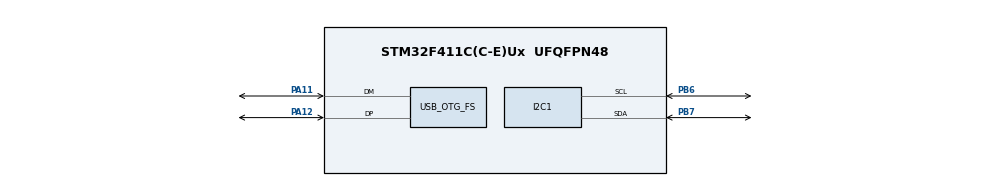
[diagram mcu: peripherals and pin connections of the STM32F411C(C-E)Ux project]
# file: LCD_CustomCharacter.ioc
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Mcu.Family=STM32F4
Mcu.Name=STM32F411C(C-E)Ux
Mcu.Package=UFQFPN48
NVIC.OTG_FS_IRQn=true\:0\:0\:false\:false\:true\:false\:true\:true
NVIC.PriorityGroup=NVIC_PRIORITYGROUP_4
PA11.Mode=Device_Only
PA11.Signal=USB_OTG_FS_DM
PA12.Mode=Device_Only
PA12.Signal=USB_OTG_FS_DP
PA13.Mode=Serial_Wire
PA13.Signal=SYS_JTMS-SWDIO
PA14.Mode=Serial_Wire
PA14.Signal=SYS_JTCK-SWCLK
PB6.Mode=I2C
PB6.Signal=I2C1_SCL
PB7.Mode=I2C
PB7.Signal=I2C1_SDA
PH0\ -\ OSC_IN.Mode=HSE-External-Oscillator
PH0\ -\ OSC_IN.Signal=RCC_OSC_IN
PH1\ -\ OSC_OUT.Mode=HSE-External-Oscillator
PH1\ -\ OSC_OUT.Signal=RCC_OSC_OUT
ProjectManager.HeapSize=0x200
ProjectManager.StackSize=0x400
ProjectManager.TargetToolchain=STM32CubeIDE
RCC.48MHZClocksFreq_Value=48000000
RCC.AHBFreq_Value=25000000
RCC.APB1CLKDivider=RCC_HCLK_DIV2
RCC.APB1Freq_Value=12500000
RCC.APB1TimFreq_Value=25000000
RCC.APB2Freq_Value=25000000
RCC.APB2TimFreq_Value=25000000
RCC.CortexFreq_Value=25000000
RCC.HCLKFreq_Value=25000000
RCC.HSE_VALUE=25000000
RCC.HSI_VALUE=16000000
RCC.LSE_VALUE=32768
RCC.PLLM=15
RCC.PLLN=144
RCC.PLLQ=5
RCC.SYSCLKFreq_VALUE=25000000
RCC.SYSCLKSource=RCC_SYSCLKSOURCE_HSE
RCC.VCOOutputFreq_Value=240000000
USB_DEVICE.CLASS_NAME_FS=CDC
USB_DEVICE.VirtualMode=Cdc
USB_DEVICE.VirtualModeFS=Cdc_FS
USB_OTG_FS.VirtualMode=Device_Only
VP_USB_DEVICE_VS_USB_DEVICE_CDC_FS.Mode=CDC_FS
board=custom

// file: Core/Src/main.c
/* USER CODE BEGIN Header */
/**
 ******************************************************************************
 * @file           : main.c
 * @brief          : Main program body
 ******************************************************************************
 * @attention
 *
 * Copyright (c) 2024 STMicroelectronics.
 * All rights reserved.
 *
 * This software is licensed under terms that can be found in the LICENSE file
 * in the root directory of this software component.
 * If no LICENSE file comes with this software, it is provided AS-IS.
 *
 ******************************************************************************
 */
/* USER CODE END Header */
#include "main.h"
#include "usb_device.h"

/* USER CODE BEGIN Includes */
#include "count2volt.h"
/* USER CODE END Includes */

/* USER CODE BEGIN PD */
#define END_I2C 0x27
#define Linha_1 (0x80 | 0x00)
#define Linha_2 (0x80 | 0x40)
#define Linha_3 (0x80 | 0x14)
#define Linha_4 (0x80 | 0x54)
#define ADCRES 12
/* USER CODE END PD */

I2C_HandleTypeDef hi2c1;

void SystemClock_Config(void);
static void MX_GPIO_Init(void);
static void MX_I2C1_Init(void);
/* USER CODE BEGIN PFP */
void create_custom_char (uint8_t loc, char *data);
void display_custom_char (uint8_t loc);
/* USER CODE END PFP */

int main(void) {

	/* MCU Configuration--------------------------------------------------------*/

	/* Reset of all peripherals, Initializes the Flash interface and the Systick. */
	HAL_Init();

	/* Configure the system clock */
	SystemClock_Config();

	/* Initialize all configured peripherals */
	MX_GPIO_Init();
	MX_I2C1_Init();
	MX_USB_DEVICE_Init();
	lcd_init();
	/* USER CODE BEGIN 2 */

	lcd_clear();

/*

	char cc1[] = { 0x00, 0x00, 0x0A, 0x00, 0x11, 0x0E, 0x00, 0x00 };  // smiley
	char cc2[] = { 0x0E, 0x0E, 0x04, 0x0E, 0x15, 0x04, 0x0A, 0x0A };  // Robo
	char cc3[] = { 0x08, 0x0C, 0x0E, 0x0F, 0x0E, 0x0C, 0x08, 0x00 };  // arrow
	char cc4[] = { 0x00, 0x04, 0x0E, 0x0E, 0x0E, 0x1F, 0x04, 0x00 };  // bell
	char cc5[] = { 0x00, 0x00, 0x0A, 0x15, 0x11, 0x0E, 0x04, 0x00 };  // Heart
	char cc6[] = { 0x00, 0x0E, 0x11, 0x11, 0x11, 0x0A, 0x1B, 0x00 };  // omega
	char cc7[] = { 0x0E, 0x10, 0x17, 0x12, 0x12, 0x12, 0x10, 0x0E };  // CT
	char cc8[] = { 0x04, 0x04, 0x1F, 0x04, 0x04, 0x00, 0x1F, 0x00 };  // +-

*/

	const char glyphs[][8] = { // Each is an eighth of the number digit                        // Custom character definitions
	      { 0x1F, 0x1F, 0x1F, 0x00, 0x00, 0x00, 0x00, 0x00 }, // char 1
	      { 0x18, 0x1C, 0x1E, 0x1F, 0x1F, 0x1F, 0x1F, 0x1F }, // char 2
	      { 0x1F, 0x1F, 0x1F, 0x1F, 0x1F, 0x0F, 0x07, 0x03 }, // char 3
	      { 0x00, 0x00, 0x00, 0x00, 0x00, 0x1F, 0x1F, 0x1F }, // char 4
	      { 0x1F, 0x1F, 0x1F, 0x1F, 0x1F, 0x1E, 0x1C, 0x18 }, // char 5
	      { 0x1F, 0x1F, 0x1F, 0x00, 0x00, 0x00, 0x1F, 0x1F }, // char 6
	      { 0x1F, 0x00, 0x00, 0x00, 0x00, 0x1F, 0x1F, 0x1F }, // char 7
	      { 0x03, 0x07, 0x0F, 0x1F, 0x1F, 0x1F, 0x1F, 0x1F }  // char 8
	};

	create_custom_char(0, glyphs[0]);
	create_custom_char(1, glyphs[1]);
	create_custom_char(2, glyphs[2]);
	create_custom_char(3, glyphs[3]);
	create_custom_char(4, glyphs[4]);
	create_custom_char(5, glyphs[5]);
	create_custom_char(6, glyphs[6]);
	create_custom_char(7, glyphs[7]);

/*

	lcd_put_cur(0, 0);
	lcd_send_string("Custom characters");
	HAL_Delay(200);
	lcd_put_cur(1, 1);

*/
	lcd_put_cur(0, 0);
	display_custom_char(7);
	lcd_put_cur(0,1);
	display_custom_char(0);
	lcd_put_cur(0, 2);
	display_custom_char(1);
	lcd_put_cur(1,0);
	display_custom_char(2);
	lcd_put_cur(1, 1);
	display_custom_char(3);
	lcd_put_cur(1, 2);
	display_custom_char(4);

/*	for (int i = 0; i < 8; i++) {
		display_custom_char(i);
		HAL_Delay(300);
	}*/

	//HAL_Delay(1000);
	//lcd_clear();
	//HAL_Delay(1000);

/*

	// store the chars into the CGRAM
	lcd_send_cmd(0x40);
	for (int i = 0; i < 8; i++)
		lcd_send_data(cc1[i]);

	lcd_send_cmd(0x40 + 8);
	for (int i = 0; i < 8; i++)
		lcd_send_data(cc2[i]);

	lcd_send_cmd(0x40 + 16);
	for (int i = 0; i < 8; i++)
		lcd_send_data(cc3[i]);

	lcd_send_cmd(0x40 + 24);
	for (int i = 0; i < 8; i++)
		lcd_send_data(cc4[i]);

	lcd_send_cmd(0x40 + 32);
	for (int i = 0; i < 8; i++)
		lcd_send_data(cc5[i]);

	lcd_send_cmd(0x40 + 40);
	for (int i = 0; i < 8; i++)
		lcd_send_data(cc6[i]);

	lcd_send_cmd(0x40 + 48);
	for (int i = 0; i < 8; i++)
		lcd_send_data(cc7[i]);

	lcd_send_cmd(0x40 + 56);
	for (int i = 0; i < 8; i++)
		lcd_send_data(cc8[i]);

*/

/*

	lcd_clear();

	for(int i = 0; i < 20; i++) {
		lcd_put_cur(0,i);
		lcd_send_data(0xFF);
		lcd_put_cur(3,i);
		lcd_send_data(0xFF);
	}

	for(int i = 1; i < 3; i++) {
		lcd_put_cur(i,0);
		lcd_send_data(0xFF);
		lcd_put_cur(i, 19);
		lcd_send_data(0xFF);
	}

	// A tabela de caracteres da CGROM é a ASCII 32=space [33,126] numbers, letters and some especial
	// characters
	for(int row = 1; row < 3; row++) {
		for(int column = 1; column < 19; column++) {
			for(int character = 33; character <= 90; character++) {
				lcd_put_cur(row, column);
				lcd_send_data(character);
				HAL_Delay(50);
			}
			lcd_put_cur(row, column);
			lcd_send_data(32);
		}
	}

*/

	/* USER CODE END 2 */

	/* Infinite loop */
	while (1) {

	}
}

void SystemClock_Config(void) {
	RCC_OscInitTypeDef RCC_OscInitStruct = { 0 };
	RCC_ClkInitTypeDef RCC_ClkInitStruct = { 0 };

	/** Configure the main internal regulator output voltage
	 */
	__HAL_RCC_PWR_CLK_ENABLE();
	__HAL_PWR_VOLTAGESCALING_CONFIG(PWR_REGULATOR_VOLTAGE_SCALE1);

	/** Initializes the RCC Oscillators according to the specified parameters
	 * in the RCC_OscInitTypeDef structure.
	 */
	RCC_OscInitStruct.OscillatorType = RCC_OSCILLATORTYPE_HSE;
	RCC_OscInitStruct.HSEState = RCC_HSE_ON;
	RCC_OscInitStruct.PLL.PLLState = RCC_PLL_ON;
	RCC_OscInitStruct.PLL.PLLSource = RCC_PLLSOURCE_HSE;
	RCC_OscInitStruct.PLL.PLLM = 12;
	RCC_OscInitStruct.PLL.PLLN = 96;
	RCC_OscInitStruct.PLL.PLLP = RCC_PLLP_DIV2;
	RCC_OscInitStruct.PLL.PLLQ = 4;
	if (HAL_RCC_OscConfig(&RCC_OscInitStruct) != HAL_OK) {
		Error_Handler();
	}

	/** Initializes the CPU, AHB and APB buses clocks
	 */
	RCC_ClkInitStruct.ClockType = RCC_CLOCKTYPE_HCLK | RCC_CLOCKTYPE_SYSCLK
			| RCC_CLOCKTYPE_PCLK1 | RCC_CLOCKTYPE_PCLK2;
	RCC_ClkInitStruct.SYSCLKSource = RCC_SYSCLKSOURCE_PLLCLK;
	RCC_ClkInitStruct.AHBCLKDivider = RCC_SYSCLK_DIV1;
	RCC_ClkInitStruct.APB1CLKDivider = RCC_HCLK_DIV2;
	RCC_ClkInitStruct.APB2CLKDivider = RCC_HCLK_DIV1;

	if (HAL_RCC_ClockConfig(&RCC_ClkInitStruct, FLASH_LATENCY_3) != HAL_OK) {
		Error_Handler();
	}
}

static void MX_I2C1_Init(void) {

	hi2c1.Instance = I2C1;
	hi2c1.Init.ClockSpeed = 100000;
	hi2c1.Init.DutyCycle = I2C_DUTYCYCLE_2;
	hi2c1.Init.OwnAddress1 = 0;
	hi2c1.Init.AddressingMode = I2C_ADDRESSINGMODE_7BIT;
	hi2c1.Init.DualAddressMode = I2C_DUALADDRESS_DISABLE;
	hi2c1.Init.OwnAddress2 = 0;
	hi2c1.Init.GeneralCallMode = I2C_GENERALCALL_DISABLE;
	hi2c1.Init.NoStretchMode = I2C_NOSTRETCH_DISABLE;
	if (HAL_I2C_Init(&hi2c1) != HAL_OK) {
		Error_Handler();
	}

}

static void MX_GPIO_Init(void) {

	/* GPIO Ports Clock Enable */
	__HAL_RCC_GPIOH_CLK_ENABLE();
	__HAL_RCC_GPIOA_CLK_ENABLE();
	__HAL_RCC_GPIOB_CLK_ENABLE();

}

/* USER CODE BEGIN 4 */

void create_custom_char (uint8_t loc, char  *data) {
	switch (loc) {
		case 0:
			lcd_send_cmd(0x40);
			break;
		case 1:
			lcd_send_cmd(0x40+8);
			break;
		case 2:
			lcd_send_cmd(0x40+16);
			break;
		case 3:
			lcd_send_cmd(0x40+24);
			break;
		case 4:
			lcd_send_cmd(0x40+32);
			break;
		case 5:
			lcd_send_cmd(0x40+40);
			break;
		case 6:
			lcd_send_cmd(0x40+48);
			break;
		case 7:
			lcd_send_cmd(0x40+56);
			break;
		default:
			break;
	}

	uint8_t cc_data[8];
	for (int i = 0; i < 8; i++) {
		cc_data[i] = *data++;
	}

	for (int i = 0; i < 8; i++) {
		lcd_send_data(cc_data[i]);
	}

}

void display_custom_char (uint8_t loc) {
	switch (loc)
			{
		case 0:
			lcd_send_data(0);
			break;
		case 1:
			lcd_send_data(1);
			break;
		case 2:
			lcd_send_data(2);
			break;
		case 3:
			lcd_send_data(3);
			break;
		case 4:
			lcd_send_data(4);
			break;
		case 5:
			lcd_send_data(5);
			break;
		case 6:
			lcd_send_data(6);
			break;
		case 7:
			lcd_send_data(7);
			break;
		default:
			break;
	}
}

/* USER CODE END 4 */

void Error_Handler(void) {
	__disable_irq();
	while (1) {
	}
}
